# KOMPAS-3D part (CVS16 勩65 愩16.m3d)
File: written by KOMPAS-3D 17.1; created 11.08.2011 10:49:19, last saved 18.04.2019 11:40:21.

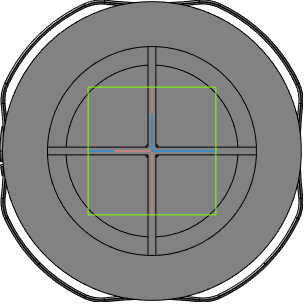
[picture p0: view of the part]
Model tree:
1. Плоскость XY
2. Плоскость ZX
3. Плоскость ZY
4. Ось X
5. Ось Y
6. Ось Z
7. Начало координат
8. Операция без истории:2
